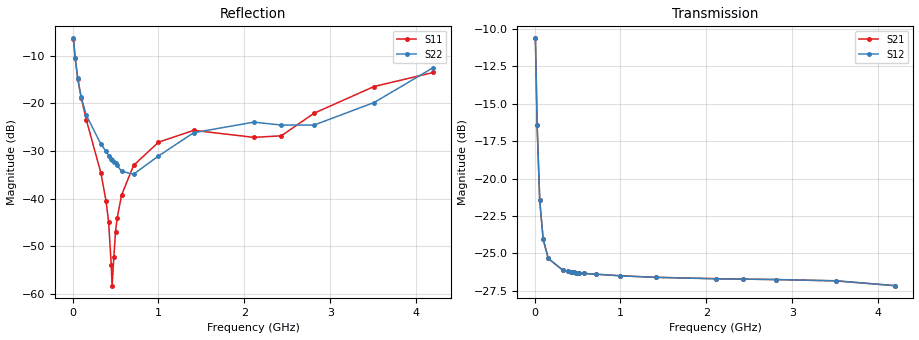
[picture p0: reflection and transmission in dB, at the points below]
! Integrated Device Technology
! Corporate Headquarters
! 6024 Silver Creek Valley Road
! San Jose, CA 95138  USA
! Phone:  1-408-284-8200
! Toll Free:  1-800-223-1366
! Webpage:  http://www.idt.com/
! Timing and RF Division
! 515 Groton Road, Suite 102
! Westford, MA 01886-6024
! Device:  F1950
! Description: 7-bit 0.25 dB Digital Step Attenuator
! Frequency:  150.0 -  4000.00 MHz
! Package:  4x4 mm Thin QFN Plastic Package: 24 pin
! Ports:  2 RF, 12 DC
!  Pin  1  = D0
!  Pin  2  = VDD
!  Pin  3  = Vmode
!  Pin  4  = GND
!  Pin  5  = RF1  =  Port 1
!  Pin  6  = GND
!  Pin  7  = GND
!  Pin  8  = GND
!  Pin  9  = GND
!  Pin 10  = GND
!  Pin 11  = GND
!  Pin 12  = GND
!  Pin 13  = GND
!  Pin 14  = RF2  =  Port 2
!  Pin 15  = GND
!  Pin 16  = LE
!  Pin 17  = CLK
!  Pin 18  = DATE
!  Pin 19  = D6
!  Pin 20  = D5
!  Pin 21  = D4
!  Pin 22  = D3
!  Pin 23  = D2
!  Pin 24  = D1
! State:  102
! Atten State:  25.50 dB
! Voltage:  +5.00 Volts
! Current:  Not Measured mA
! Data:  The device was measured on a the F195X evaluation board which has
!  individual transmission lines to the RF pins.  Data was collected
!  using a calibrated network analyzer.  The evaluation board was
!  de-embedded using a TRL calibration technique.
!  The reference plane is the edge of the package pin.
! Misc:  Board 2019
!  Action Tracker AT0250
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# GHz S dB R 50
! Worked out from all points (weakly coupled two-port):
!   420 points, 10 MHz to 4.2 GHz, reference 50 ohm
!   highest |S21| = -10.62 dB at 10 MHz (marker M1); lowest = -27.2 dB at 4.2 GHz (marker M2)
!   lowest |S11| = -58.3 dB at 460 MHz (marker M3), VSWR 1.00, Z = 49.9 - j0.0867 ohm
!   |S11| at or under -10 dB: 27.5 MHz to end of sweep
!   |S22| runs from -35.1 to -6.4 dB; largest |S21 - S12| = 0.0001
!   S11 on the Smith chart (normalised r, x): 10 MHz: 2.05, -1.14; 30 MHz: 1.29, -0.65; 60 MHz: 1.11, -0.37; 390 MHz: 1.01, -0.02; 4.2 GHz: 0.69, +0.17
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0.01  -6.45 -26.9  -10.62 -34.3  -10.62 -34.3  -6.37 -27.8
0.03  -10.48 -50.4  -16.43 -53.5  -16.43 -53.5  -10.40 -51.8
0.06  -14.91 -63.5  -21.44 -49.3  -21.44 -49.3  -14.69 -65.0
0.1  -18.79 -70.2  -24.06 -37.8  -24.05 -37.8  -18.76 -70.5
0.16  -23.46 -71.9  -25.34 -27.2  -25.34 -27.2  -22.48 -75.4
0.33  -34.65 -69.8  -26.13 -16.9  -26.12 -16.9  -28.55 -83.5
0.39  -40.53 -69.0  -26.20 -15.7  -26.21 -15.7  -30.09 -85.9
0.42  -44.99 -75.7  -26.24 -15.2  -26.24 -15.3  -30.95 -87.9
0.45  -53.92 -96.7  -26.27 -14.9  -26.26 -14.9  -31.70 -92.3
0.46  -58.26 -134.7  -26.27 -14.8  -26.27 -14.8  -31.90 -93.9
0.48  -52.34 149.1  -26.29 -14.7  -26.28 -14.7  -32.22 -96.8
0.5  -46.91 138.8  -26.30 -14.5  -26.29 -14.5  -32.55 -98.6
0.52  -43.98 137.6  -26.31 -14.4  -26.31 -14.4  -33.00 -100.1
0.57  -39.27 133.3  -26.34 -14.3  -26.34 -14.3  -34.28 -109.6
0.71  -33.02 137.1  -26.39 -14.3  -26.39 -14.3  -34.86 -137.3
1  -28.15 147.4  -26.50 -15.7  -26.50 -15.7  -31.05 -179.9
1.41  -25.67 162.7  -26.60 -18.5  -26.60 -18.5  -26.16 161.0
2.11  -27.14 157.4  -26.69 -24.5  -26.70 -24.5  -23.95 142.6
2.43  -26.82 125.4  -26.72 -27.1  -26.72 -27.1  -24.56 131.9
2.81  -22.09 104.7  -26.75 -30.8  -26.75 -30.9  -24.57 116.5
3.51  -16.47 117.0  -26.84 -37.2  -26.83 -37.2  -19.83 113.7
4.2  -13.53 145.5  -27.16 -41.3  -27.16 -41.4  -12.50 127.4
